VERSION 5.7 ;
BUSBITCHARS "[]" ;
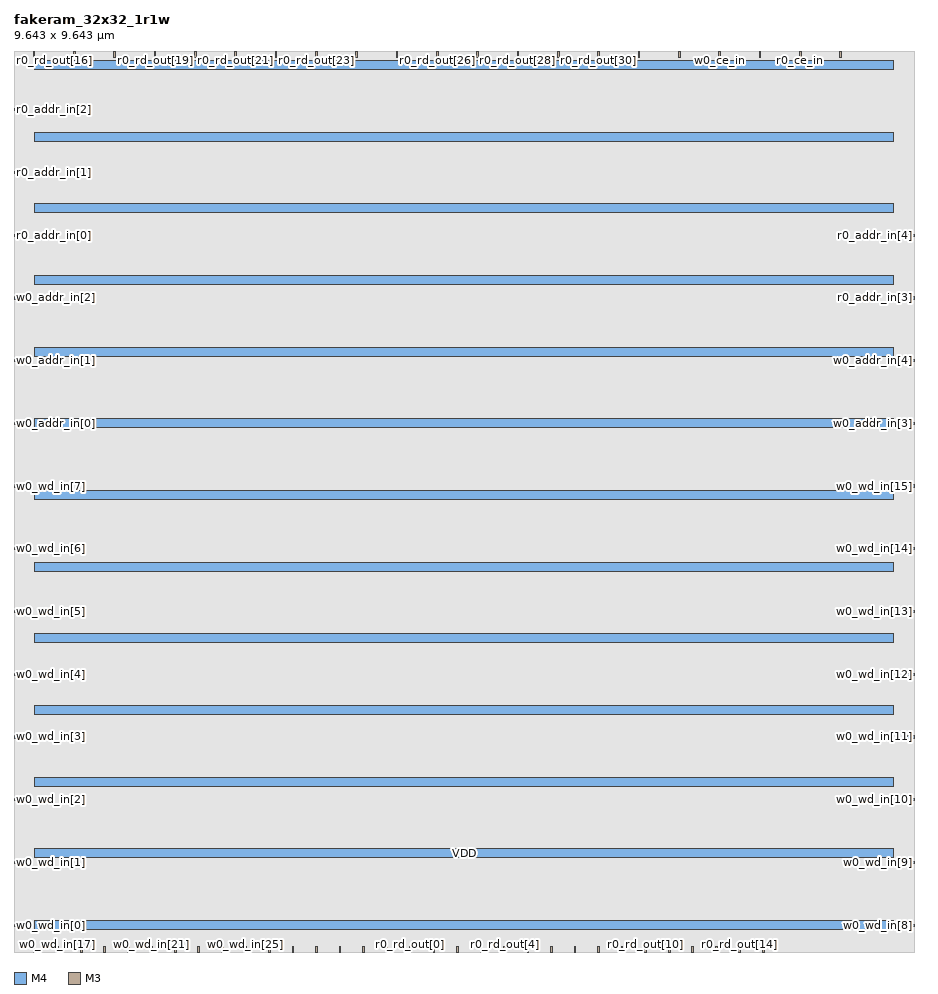
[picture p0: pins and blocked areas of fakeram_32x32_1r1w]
MACRO fakeram_32x32_1r1w
  FOREIGN fakeram_32x32_1r1w 0 0 ;
  SYMMETRY X Y R90 ;
  SIZE 9.643 BY 9.643 ;
  CLASS BLOCK ;
  PIN w0_wd_in[0]
    DIRECTION INPUT ;
    USE SIGNAL ;
    SHAPE ABUTMENT ;
    PORT
      LAYER M4 ;
      RECT 0.000 0.276 0.072 0.300 ;
    END
  END w0_wd_in[0]
  PIN w0_wd_in[1]
    DIRECTION INPUT ;
    USE SIGNAL ;
    SHAPE ABUTMENT ;
    PORT
      LAYER M4 ;
      RECT 0.000 0.948 0.072 0.972 ;
    END
  END w0_wd_in[1]
  PIN w0_wd_in[2]
    DIRECTION INPUT ;
    USE SIGNAL ;
    SHAPE ABUTMENT ;
    PORT
      LAYER M4 ;
      RECT 0.000 1.620 0.072 1.644 ;
    END
  END w0_wd_in[2]
  PIN w0_wd_in[3]
    DIRECTION INPUT ;
    USE SIGNAL ;
    SHAPE ABUTMENT ;
    PORT
      LAYER M4 ;
      RECT 0.000 2.292 0.072 2.316 ;
    END
  END w0_wd_in[3]
  PIN w0_wd_in[4]
    DIRECTION INPUT ;
    USE SIGNAL ;
    SHAPE ABUTMENT ;
    PORT
      LAYER M4 ;
      RECT 0.000 2.964 0.072 2.988 ;
    END
  END w0_wd_in[4]
  PIN w0_wd_in[5]
    DIRECTION INPUT ;
    USE SIGNAL ;
    SHAPE ABUTMENT ;
    PORT
      LAYER M4 ;
      RECT 0.000 3.636 0.072 3.660 ;
    END
  END w0_wd_in[5]
  PIN w0_wd_in[6]
    DIRECTION INPUT ;
    USE SIGNAL ;
    SHAPE ABUTMENT ;
    PORT
      LAYER M4 ;
      RECT 0.000 4.308 0.072 4.332 ;
    END
  END w0_wd_in[6]
  PIN w0_wd_in[7]
    DIRECTION INPUT ;
    USE SIGNAL ;
    SHAPE ABUTMENT ;
    PORT
      LAYER M4 ;
      RECT 0.000 4.980 0.072 5.004 ;
    END
  END w0_wd_in[7]
  PIN w0_wd_in[8]
    DIRECTION INPUT ;
    USE SIGNAL ;
    SHAPE ABUTMENT ;
    PORT
      LAYER M4 ;
      RECT 9.571 0.276 9.643 0.300 ;
    END
  END w0_wd_in[8]
  PIN w0_wd_in[9]
    DIRECTION INPUT ;
    USE SIGNAL ;
    SHAPE ABUTMENT ;
    PORT
      LAYER M4 ;
      RECT 9.571 0.948 9.643 0.972 ;
    END
  END w0_wd_in[9]
  PIN w0_wd_in[10]
    DIRECTION INPUT ;
    USE SIGNAL ;
    SHAPE ABUTMENT ;
    PORT
      LAYER M4 ;
      RECT 9.571 1.620 9.643 1.644 ;
    END
  END w0_wd_in[10]
  PIN w0_wd_in[11]
    DIRECTION INPUT ;
    USE SIGNAL ;
    SHAPE ABUTMENT ;
    PORT
      LAYER M4 ;
      RECT 9.571 2.292 9.643 2.316 ;
    END
  END w0_wd_in[11]
  PIN w0_wd_in[12]
    DIRECTION INPUT ;
    USE SIGNAL ;
    SHAPE ABUTMENT ;
    PORT
      LAYER M4 ;
      RECT 9.571 2.964 9.643 2.988 ;
    END
  END w0_wd_in[12]
  PIN w0_wd_in[13]
    DIRECTION INPUT ;
    USE SIGNAL ;
    SHAPE ABUTMENT ;
    PORT
      LAYER M4 ;
      RECT 9.571 3.636 9.643 3.660 ;
    END
  END w0_wd_in[13]
  PIN w0_wd_in[14]
    DIRECTION INPUT ;
    USE SIGNAL ;
    SHAPE ABUTMENT ;
    PORT
      LAYER M4 ;
      RECT 9.571 4.308 9.643 4.332 ;
    END
  END w0_wd_in[14]
  PIN w0_wd_in[15]
    DIRECTION INPUT ;
    USE SIGNAL ;
    SHAPE ABUTMENT ;
    PORT
      LAYER M4 ;
      RECT 9.571 4.980 9.643 5.004 ;
    END
  END w0_wd_in[15]
  PIN w0_wd_in[16]
    DIRECTION OUTPUT ;
    USE SIGNAL ;
    SHAPE ABUTMENT ;
    PORT
      LAYER M3 ;
      RECT 0.207 0.000 0.225 0.054 ;
    END
  END w0_wd_in[16]
  PIN w0_wd_in[17]
    DIRECTION OUTPUT ;
    USE SIGNAL ;
    SHAPE ABUTMENT ;
    PORT
      LAYER M3 ;
      RECT 0.459 0.000 0.477 0.054 ;
    END
  END w0_wd_in[17]
  PIN w0_wd_in[18]
    DIRECTION OUTPUT ;
    USE SIGNAL ;
    SHAPE ABUTMENT ;
    PORT
      LAYER M3 ;
      RECT 0.711 0.000 0.729 0.054 ;
    END
  END w0_wd_in[18]
  PIN w0_wd_in[19]
    DIRECTION OUTPUT ;
    USE SIGNAL ;
    SHAPE ABUTMENT ;
    PORT
      LAYER M3 ;
      RECT 0.963 0.000 0.981 0.054 ;
    END
  END w0_wd_in[19]
  PIN w0_wd_in[20]
    DIRECTION OUTPUT ;
    USE SIGNAL ;
    SHAPE ABUTMENT ;
    PORT
      LAYER M3 ;
      RECT 1.215 0.000 1.233 0.054 ;
    END
  END w0_wd_in[20]
  PIN w0_wd_in[21]
    DIRECTION OUTPUT ;
    USE SIGNAL ;
    SHAPE ABUTMENT ;
    PORT
      LAYER M3 ;
      RECT 1.467 0.000 1.485 0.054 ;
    END
  END w0_wd_in[21]
  PIN w0_wd_in[22]
    DIRECTION OUTPUT ;
    USE SIGNAL ;
    SHAPE ABUTMENT ;
    PORT
      LAYER M3 ;
      RECT 1.719 0.000 1.737 0.054 ;
    END
  END w0_wd_in[22]
  PIN w0_wd_in[23]
    DIRECTION OUTPUT ;
    USE SIGNAL ;
    SHAPE ABUTMENT ;
    PORT
      LAYER M3 ;
      RECT 1.971 0.000 1.989 0.054 ;
    END
  END w0_wd_in[23]
  PIN w0_wd_in[24]
    DIRECTION OUTPUT ;
    USE SIGNAL ;
    SHAPE ABUTMENT ;
    PORT
      LAYER M3 ;
      RECT 2.223 0.000 2.241 0.054 ;
    END
  END w0_wd_in[24]
  PIN w0_wd_in[25]
    DIRECTION OUTPUT ;
    USE SIGNAL ;
    SHAPE ABUTMENT ;
    PORT
      LAYER M3 ;
      RECT 2.475 0.000 2.493 0.054 ;
    END
  END w0_wd_in[25]
  PIN w0_wd_in[26]
    DIRECTION OUTPUT ;
    USE SIGNAL ;
    SHAPE ABUTMENT ;
    PORT
      LAYER M3 ;
      RECT 2.727 0.000 2.745 0.054 ;
    END
  END w0_wd_in[26]
  PIN w0_wd_in[27]
    DIRECTION OUTPUT ;
    USE SIGNAL ;
    SHAPE ABUTMENT ;
    PORT
      LAYER M3 ;
      RECT 2.979 0.000 2.997 0.054 ;
    END
  END w0_wd_in[27]
  PIN w0_wd_in[28]
    DIRECTION OUTPUT ;
    USE SIGNAL ;
    SHAPE ABUTMENT ;
    PORT
      LAYER M3 ;
      RECT 3.231 0.000 3.249 0.054 ;
    END
  END w0_wd_in[28]
  PIN w0_wd_in[29]
    DIRECTION OUTPUT ;
    USE SIGNAL ;
    SHAPE ABUTMENT ;
    PORT
      LAYER M3 ;
      RECT 3.483 0.000 3.501 0.054 ;
    END
  END w0_wd_in[29]
  PIN w0_wd_in[30]
    DIRECTION OUTPUT ;
    USE SIGNAL ;
    SHAPE ABUTMENT ;
    PORT
      LAYER M3 ;
      RECT 3.735 0.000 3.753 0.054 ;
    END
  END w0_wd_in[30]
  PIN w0_wd_in[31]
    DIRECTION OUTPUT ;
    USE SIGNAL ;
    SHAPE ABUTMENT ;
    PORT
      LAYER M3 ;
      RECT 3.987 0.000 4.005 0.054 ;
    END
  END w0_wd_in[31]
  PIN r0_rd_out[0]
    DIRECTION OUTPUT ;
    USE SIGNAL ;
    SHAPE ABUTMENT ;
    PORT
      LAYER M3 ;
      RECT 4.239 0.000 4.257 0.054 ;
    END
  END r0_rd_out[0]
  PIN r0_rd_out[1]
    DIRECTION OUTPUT ;
    USE SIGNAL ;
    SHAPE ABUTMENT ;
    PORT
      LAYER M3 ;
      RECT 4.491 0.000 4.509 0.054 ;
    END
  END r0_rd_out[1]
  PIN r0_rd_out[2]
    DIRECTION OUTPUT ;
    USE SIGNAL ;
    SHAPE ABUTMENT ;
    PORT
      LAYER M3 ;
      RECT 4.743 0.000 4.761 0.054 ;
    END
  END r0_rd_out[2]
  PIN r0_rd_out[3]
    DIRECTION OUTPUT ;
    USE SIGNAL ;
    SHAPE ABUTMENT ;
    PORT
      LAYER M3 ;
      RECT 4.995 0.000 5.013 0.054 ;
    END
  END r0_rd_out[3]
  PIN r0_rd_out[4]
    DIRECTION OUTPUT ;
    USE SIGNAL ;
    SHAPE ABUTMENT ;
    PORT
      LAYER M3 ;
      RECT 5.247 0.000 5.265 0.054 ;
    END
  END r0_rd_out[4]
  PIN r0_rd_out[5]
    DIRECTION OUTPUT ;
    USE SIGNAL ;
    SHAPE ABUTMENT ;
    PORT
      LAYER M3 ;
      RECT 5.499 0.000 5.517 0.054 ;
    END
  END r0_rd_out[5]
  PIN r0_rd_out[6]
    DIRECTION OUTPUT ;
    USE SIGNAL ;
    SHAPE ABUTMENT ;
    PORT
      LAYER M3 ;
      RECT 5.751 0.000 5.769 0.054 ;
    END
  END r0_rd_out[6]
  PIN r0_rd_out[7]
    DIRECTION OUTPUT ;
    USE SIGNAL ;
    SHAPE ABUTMENT ;
    PORT
      LAYER M3 ;
      RECT 6.003 0.000 6.021 0.054 ;
    END
  END r0_rd_out[7]
  PIN r0_rd_out[8]
    DIRECTION OUTPUT ;
    USE SIGNAL ;
    SHAPE ABUTMENT ;
    PORT
      LAYER M3 ;
      RECT 6.255 0.000 6.273 0.054 ;
    END
  END r0_rd_out[8]
  PIN r0_rd_out[9]
    DIRECTION OUTPUT ;
    USE SIGNAL ;
    SHAPE ABUTMENT ;
    PORT
      LAYER M3 ;
      RECT 6.507 0.000 6.525 0.054 ;
    END
  END r0_rd_out[9]
  PIN r0_rd_out[10]
    DIRECTION OUTPUT ;
    USE SIGNAL ;
    SHAPE ABUTMENT ;
    PORT
      LAYER M3 ;
      RECT 6.759 0.000 6.777 0.054 ;
    END
  END r0_rd_out[10]
  PIN r0_rd_out[11]
    DIRECTION OUTPUT ;
    USE SIGNAL ;
    SHAPE ABUTMENT ;
    PORT
      LAYER M3 ;
      RECT 7.011 0.000 7.029 0.054 ;
    END
  END r0_rd_out[11]
  PIN r0_rd_out[12]
    DIRECTION OUTPUT ;
    USE SIGNAL ;
    SHAPE ABUTMENT ;
    PORT
      LAYER M3 ;
      RECT 7.263 0.000 7.281 0.054 ;
    END
  END r0_rd_out[12]
  PIN r0_rd_out[13]
    DIRECTION OUTPUT ;
    USE SIGNAL ;
    SHAPE ABUTMENT ;
    PORT
      LAYER M3 ;
      RECT 7.515 0.000 7.533 0.054 ;
    END
  END r0_rd_out[13]
  PIN r0_rd_out[14]
    DIRECTION OUTPUT ;
    USE SIGNAL ;
    SHAPE ABUTMENT ;
    PORT
      LAYER M3 ;
      RECT 7.767 0.000 7.785 0.054 ;
    END
  END r0_rd_out[14]
  PIN r0_rd_out[15]
    DIRECTION OUTPUT ;
    USE SIGNAL ;
    SHAPE ABUTMENT ;
    PORT
      LAYER M3 ;
      RECT 8.019 0.000 8.037 0.054 ;
    END
  END r0_rd_out[15]
  PIN r0_rd_out[16]
    DIRECTION OUTPUT ;
    USE SIGNAL ;
    SHAPE ABUTMENT ;
    PORT
      LAYER M3 ;
      RECT 0.207 9.589 0.225 9.643 ;
    END
  END r0_rd_out[16]
  PIN r0_rd_out[17]
    DIRECTION OUTPUT ;
    USE SIGNAL ;
    SHAPE ABUTMENT ;
    PORT
      LAYER M3 ;
      RECT 0.639 9.589 0.657 9.643 ;
    END
  END r0_rd_out[17]
  PIN r0_rd_out[18]
    DIRECTION OUTPUT ;
    USE SIGNAL ;
    SHAPE ABUTMENT ;
    PORT
      LAYER M3 ;
      RECT 1.071 9.589 1.089 9.643 ;
    END
  END r0_rd_out[18]
  PIN r0_rd_out[19]
    DIRECTION OUTPUT ;
    USE SIGNAL ;
    SHAPE ABUTMENT ;
    PORT
      LAYER M3 ;
      RECT 1.503 9.589 1.521 9.643 ;
    END
  END r0_rd_out[19]
  PIN r0_rd_out[20]
    DIRECTION OUTPUT ;
    USE SIGNAL ;
    SHAPE ABUTMENT ;
    PORT
      LAYER M3 ;
      RECT 1.935 9.589 1.953 9.643 ;
    END
  END r0_rd_out[20]
  PIN r0_rd_out[21]
    DIRECTION OUTPUT ;
    USE SIGNAL ;
    SHAPE ABUTMENT ;
    PORT
      LAYER M3 ;
      RECT 2.367 9.589 2.385 9.643 ;
    END
  END r0_rd_out[21]
  PIN r0_rd_out[22]
    DIRECTION OUTPUT ;
    USE SIGNAL ;
    SHAPE ABUTMENT ;
    PORT
      LAYER M3 ;
      RECT 2.799 9.589 2.817 9.643 ;
    END
  END r0_rd_out[22]
  PIN r0_rd_out[23]
    DIRECTION OUTPUT ;
    USE SIGNAL ;
    SHAPE ABUTMENT ;
    PORT
      LAYER M3 ;
      RECT 3.231 9.589 3.249 9.643 ;
    END
  END r0_rd_out[23]
  PIN r0_rd_out[24]
    DIRECTION OUTPUT ;
    USE SIGNAL ;
    SHAPE ABUTMENT ;
    PORT
      LAYER M3 ;
      RECT 3.663 9.589 3.681 9.643 ;
    END
  END r0_rd_out[24]
  PIN r0_rd_out[25]
    DIRECTION OUTPUT ;
    USE SIGNAL ;
    SHAPE ABUTMENT ;
    PORT
      LAYER M3 ;
      RECT 4.095 9.589 4.113 9.643 ;
    END
  END r0_rd_out[25]
  PIN r0_rd_out[26]
    DIRECTION OUTPUT ;
    USE SIGNAL ;
    SHAPE ABUTMENT ;
    PORT
      LAYER M3 ;
      RECT 4.527 9.589 4.545 9.643 ;
    END
  END r0_rd_out[26]
  PIN r0_rd_out[27]
    DIRECTION OUTPUT ;
    USE SIGNAL ;
    SHAPE ABUTMENT ;
    PORT
      LAYER M3 ;
      RECT 4.959 9.589 4.977 9.643 ;
    END
  END r0_rd_out[27]
  PIN r0_rd_out[28]
    DIRECTION OUTPUT ;
    USE SIGNAL ;
    SHAPE ABUTMENT ;
    PORT
      LAYER M3 ;
      RECT 5.391 9.589 5.409 9.643 ;
    END
  END r0_rd_out[28]
  PIN r0_rd_out[29]
    DIRECTION OUTPUT ;
    USE SIGNAL ;
    SHAPE ABUTMENT ;
    PORT
      LAYER M3 ;
      RECT 5.823 9.589 5.841 9.643 ;
    END
  END r0_rd_out[29]
  PIN r0_rd_out[30]
    DIRECTION OUTPUT ;
    USE SIGNAL ;
    SHAPE ABUTMENT ;
    PORT
      LAYER M3 ;
      RECT 6.255 9.589 6.273 9.643 ;
    END
  END r0_rd_out[30]
  PIN r0_rd_out[31]
    DIRECTION OUTPUT ;
    USE SIGNAL ;
    SHAPE ABUTMENT ;
    PORT
      LAYER M3 ;
      RECT 6.687 9.589 6.705 9.643 ;
    END
  END r0_rd_out[31]
  PIN w0_addr_in[0]
    DIRECTION INPUT ;
    USE SIGNAL ;
    SHAPE ABUTMENT ;
    PORT
      LAYER M4 ;
      RECT 0.000 5.652 0.072 5.676 ;
    END
  END w0_addr_in[0]
  PIN w0_addr_in[1]
    DIRECTION INPUT ;
    USE SIGNAL ;
    SHAPE ABUTMENT ;
    PORT
      LAYER M4 ;
      RECT 0.000 6.324 0.072 6.348 ;
    END
  END w0_addr_in[1]
  PIN w0_addr_in[2]
    DIRECTION INPUT ;
    USE SIGNAL ;
    SHAPE ABUTMENT ;
    PORT
      LAYER M4 ;
      RECT 0.000 6.996 0.072 7.020 ;
    END
  END w0_addr_in[2]
  PIN w0_addr_in[3]
    DIRECTION INPUT ;
    USE SIGNAL ;
    SHAPE ABUTMENT ;
    PORT
      LAYER M4 ;
      RECT 9.571 5.652 9.643 5.676 ;
    END
  END w0_addr_in[3]
  PIN w0_addr_in[4]
    DIRECTION INPUT ;
    USE SIGNAL ;
    SHAPE ABUTMENT ;
    PORT
      LAYER M4 ;
      RECT 9.571 6.324 9.643 6.348 ;
    END
  END w0_addr_in[4]
  PIN r0_addr_in[0]
    DIRECTION INPUT ;
    USE SIGNAL ;
    SHAPE ABUTMENT ;
    PORT
      LAYER M4 ;
      RECT 0.000 7.668 0.072 7.692 ;
    END
  END r0_addr_in[0]
  PIN r0_addr_in[1]
    DIRECTION INPUT ;
    USE SIGNAL ;
    SHAPE ABUTMENT ;
    PORT
      LAYER M4 ;
      RECT 0.000 8.340 0.072 8.364 ;
    END
  END r0_addr_in[1]
  PIN r0_addr_in[2]
    DIRECTION INPUT ;
    USE SIGNAL ;
    SHAPE ABUTMENT ;
    PORT
      LAYER M4 ;
      RECT 0.000 9.012 0.072 9.036 ;
    END
  END r0_addr_in[2]
  PIN r0_addr_in[3]
    DIRECTION INPUT ;
    USE SIGNAL ;
    SHAPE ABUTMENT ;
    PORT
      LAYER M4 ;
      RECT 9.571 6.996 9.643 7.020 ;
    END
  END r0_addr_in[3]
  PIN r0_addr_in[4]
    DIRECTION INPUT ;
    USE SIGNAL ;
    SHAPE ABUTMENT ;
    PORT
      LAYER M4 ;
      RECT 9.571 7.668 9.643 7.692 ;
    END
  END r0_addr_in[4]
  PIN w0_we_in
    DIRECTION INPUT ;
    USE SIGNAL ;
    SHAPE ABUTMENT ;
    PORT
      LAYER M3 ;
      RECT 7.119 9.589 7.137 9.643 ;
    END
  END w0_we_in
  PIN w0_ce_in
    DIRECTION INPUT ;
    USE SIGNAL ;
    SHAPE ABUTMENT ;
    PORT
      LAYER M3 ;
      RECT 7.551 9.589 7.569 9.643 ;
    END
  END w0_ce_in
  PIN w0_clk
    DIRECTION INPUT ;
    USE SIGNAL ;
    SHAPE ABUTMENT ;
    PORT
      LAYER M3 ;
      RECT 7.983 9.589 8.001 9.643 ;
    END
  END w0_clk
  PIN r0_ce_in
    DIRECTION INPUT ;
    USE SIGNAL ;
    SHAPE ABUTMENT ;
    PORT
      LAYER M3 ;
      RECT 8.415 9.589 8.433 9.643 ;
    END
  END r0_ce_in
  PIN r0_clk
    DIRECTION INPUT ;
    USE SIGNAL ;
    SHAPE ABUTMENT ;
    PORT
      LAYER M3 ;
      RECT 8.847 9.589 8.865 9.643 ;
    END
  END r0_clk
  PIN VSS
    DIRECTION INOUT ;
    USE GROUND ;
    PORT
      LAYER M4 ;
      RECT 0.216 0.240 9.427 0.336 ;
      RECT 0.216 1.008 9.427 1.104 ;
      RECT 0.216 1.776 9.427 1.872 ;
      RECT 0.216 2.544 9.427 2.640 ;
      RECT 0.216 3.312 9.427 3.408 ;
      RECT 0.216 4.080 9.427 4.176 ;
      RECT 0.216 4.848 9.427 4.944 ;
      RECT 0.216 5.616 9.427 5.712 ;
      RECT 0.216 6.384 9.427 6.480 ;
      RECT 0.216 7.152 9.427 7.248 ;
      RECT 0.216 7.920 9.427 8.016 ;
      RECT 0.216 8.688 9.427 8.784 ;
      RECT 0.216 9.456 9.427 9.552 ;
    END
  END VSS
  PIN VDD
    DIRECTION INOUT ;
    USE POWER ;
    PORT
      LAYER M4 ;
      RECT 0.216 0.240 9.427 0.336 ;
      RECT 0.216 1.008 9.427 1.104 ;
      RECT 0.216 1.776 9.427 1.872 ;
      RECT 0.216 2.544 9.427 2.640 ;
      RECT 0.216 3.312 9.427 3.408 ;
      RECT 0.216 4.080 9.427 4.176 ;
      RECT 0.216 4.848 9.427 4.944 ;
      RECT 0.216 5.616 9.427 5.712 ;
      RECT 0.216 6.384 9.427 6.480 ;
      RECT 0.216 7.152 9.427 7.248 ;
      RECT 0.216 7.920 9.427 8.016 ;
      RECT 0.216 8.688 9.427 8.784 ;
      RECT 0.216 9.456 9.427 9.552 ;
    END
  END VDD
  OBS
    LAYER M1 ;
    RECT 0 0 9.643 9.643 ;
    LAYER M2 ;
    RECT 0 0 9.643 9.643 ;
    LAYER M3 ;
    RECT 0 0 9.643 9.643 ;
    LAYER M4 ;
    RECT 0 0 9.643 9.643 ;
  END
END fakeram_32x32_1r1w

END LIBRARY
